! (c) 2009  Infineon Technologies AG, Munich
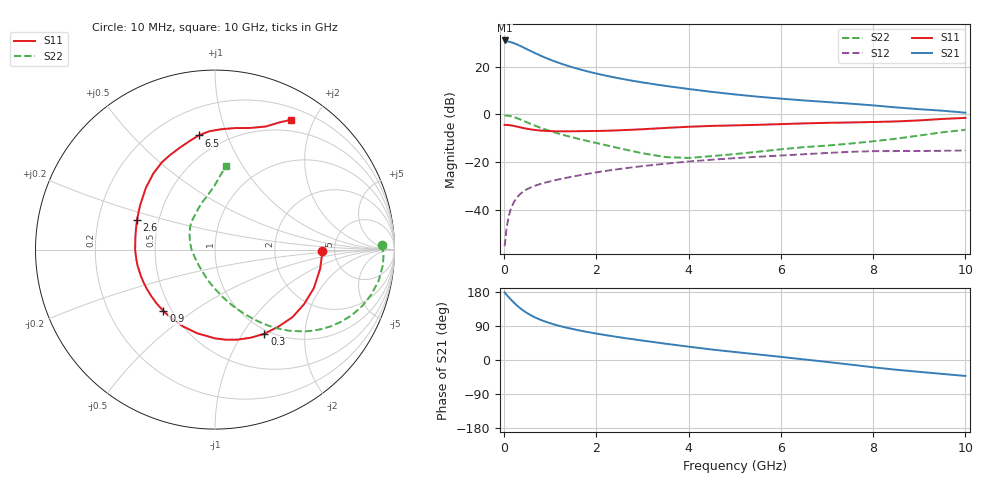
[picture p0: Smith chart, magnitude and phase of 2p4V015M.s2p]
! Infineon Technologies  Discrete & RF Semiconductors
! BFP420
! VCE =  4.0 V,  IC =  15 mA
! Common Emitter S-Parameters:  Nov 2009
# GHz  S  MA  R  50
!  f  S11  S21  S12  S22
! GHz  MAG  ANG  MAG  ANG  MAG  ANG  MAG  ANG
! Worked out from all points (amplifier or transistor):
!   46 points, 10 MHz to 10 GHz, reference 50 ohm
!   highest |S21| = 31.0 dB at 10 MHz (marker M1)
!   |S21| within 3 dB of that: start of sweep to 425.1 MHz
!   unconditionally stable (mu >= 1): start of sweep to 17.63 MHz; 2.058 GHz to end of sweep
!   at 300 MHz: K = 0.31, MSG = 31.8 dB, |S12| = -34.4 dB
!   at 1.7 GHz: K = 0.92, MSG = 22.0 dB, |S12| = -25.4 dB
!   at 10 GHz: K = 1.08, MAG = 6.2 dB, |S12| = -15.2 dB
!   lowest NFmin = 1.06 dB at 900 MHz
!   S11 on the Smith chart (normalised r, x): 10 MHz: 3.98, -0.13; 300 MHz: 0.95, -1.26; 900 MHz: 0.45, -0.39; 2.6 GHz: 0.38, +0.16; 6.5 GHz: 0.37, +0.80; 10 GHz: 0.35, +1.69
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0.01  0.599 -1.0  35.35 178.5  0.0017 38.3  0.929 1.6
0.02  0.5959 -4.1  34.29 176.6  0.002 48.6  0.9392 -1.7
0.1  0.5912 -21.2  33.43 165.6  0.0073 71.1  0.9281 -10.7
0.15  0.5821 -31.4  32.47 159.0  0.0106 70.6  0.9066 -16.0
0.2  0.5727 -41.2  31.31 152.9  0.0136 68.5  0.8784 -20.9
0.25  0.5559 -50.6  29.89 146.9  0.0164 66.3  0.8464 -25.5
0.3  0.5435 -59.6  28.57 141.5  0.019 63.7  0.8111 -29.6
0.35  0.5297 -67.9  27.14 136.5  0.0213 61.6  0.7753 -33.4
0.45  0.506 -83.0  24.36 127.6  0.0251 58.0  0.7054 -39.9
0.6  0.4768 -102.0  20.66 116.6  0.0298 54.2  0.6123 -47.6
0.7  0.4635 -112.7  18.59 110.7  0.0323 52.6  0.5604 -51.6
0.9  0.4469 -130.0  15.27 101.0  0.0369 50.6  0.477 -58.1
1.2  0.4386 -149.8  11.84 89.9  0.0432 49.3  0.3866 -66.1
1.7  0.4417 -172.6  8.439 76.4  0.0537 47.8  0.2899 -77.4
2.2  0.4495 170.5  6.469 65.7  0.0645 45.7  0.2247 -88.6
2.6  0.4649 159.1  5.421 58.1  0.0729 43.3  0.1835 -100.0
3.5  0.5155 138.5  3.929 43.0  0.0917 37.0  0.1262 -136.0
5.5  0.5992 109.5  2.337 14.7  0.1278 20.6  0.1631 150.3
6.5  0.6424 98.2  1.948 1.6  0.1446 12.2  0.2039 130.1
7  0.66 92.8  1.802 -5.1  0.1536 7.7  0.2195 121.3
8.5  0.7061 73.7  1.391 -25.7  0.1687 -8.7  0.3067 97.4
10  0.8375 59.7  1.076 -42.1  0.1732 -19.6  0.4701 82.4
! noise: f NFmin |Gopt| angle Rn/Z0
0.9  1.06  0.09  -152  0.13
1.8  1.36  0.18  -147  0.12
2.4  1.49  0.17  -148  0.14
3  1.53  0.25  -138  0.14
4  1.67  0.38  -119  0.2
5  2.14  0.44  -103  0.32
6  2.48  0.5  -88  0.47
